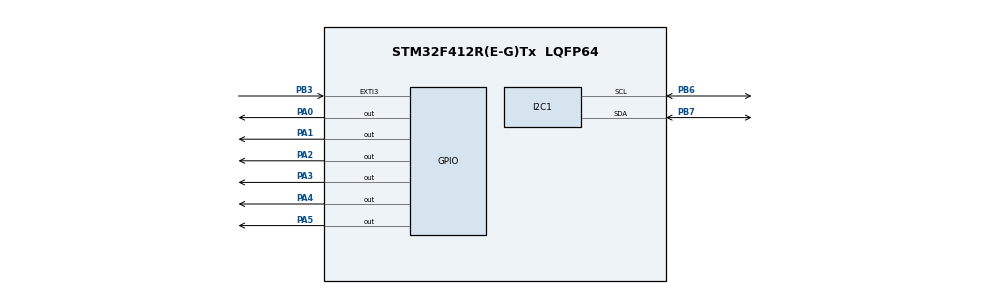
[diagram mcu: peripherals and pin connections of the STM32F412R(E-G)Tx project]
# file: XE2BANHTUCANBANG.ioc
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Mcu.Family=STM32F4
Mcu.Name=STM32F412R(E-G)Tx
Mcu.Package=LQFP64
NVIC.PriorityGroup=NVIC_PRIORITYGROUP_4
PA0.Signal=GPIO_Output
PA1.Signal=GPIO_Output
PA2.Signal=GPIO_Output
PA3.Signal=GPIO_Output
PA4.Signal=GPIO_Output
PA5.Signal=GPIO_Output
PB3.Signal=GPXTI3
PB6.Mode=I2C
PB6.Signal=I2C1_SCL
PB7.Mode=I2C
PB7.Signal=I2C1_SDA
PC14-OSC32_IN.Mode=LSE-External-Oscillator
PC14-OSC32_IN.Signal=RCC_OSC32_IN
PC15-OSC32_OUT.Mode=LSE-External-Oscillator
PC15-OSC32_OUT.Signal=RCC_OSC32_OUT
PH0\ -\ OSC_IN.Mode=HSE-External-Oscillator
PH0\ -\ OSC_IN.Signal=RCC_OSC_IN
PH1\ -\ OSC_OUT.Mode=HSE-External-Oscillator
PH1\ -\ OSC_OUT.Signal=RCC_OSC_OUT
ProjectManager.HeapSize=0x200
ProjectManager.StackSize=0x400
ProjectManager.TargetToolchain=CMake
RCC.AHBFreq_Value=64000000
RCC.APB1CLKDivider=RCC_HCLK_DIV2
RCC.APB1Freq_Value=32000000
RCC.APB1TimFreq_Value=64000000
RCC.APB2CLKDivider=RCC_HCLK_DIV2
RCC.APB2Freq_Value=32000000
RCC.APB2TimFreq_Value=64000000
RCC.CortexFreq_Value=64000000
RCC.HCLKFreq_Value=64000000
RCC.HSE_VALUE=8000000
RCC.PLLM=8
RCC.PLLN=64
RCC.SYSCLKFreq_VALUE=64000000
RCC.SYSCLKSource=RCC_SYSCLKSOURCE_PLLCLK
RCC.USBFreq_Value=64000000
RCC.VCOOutputFreq_Value=128000000
board=custom

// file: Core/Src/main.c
/* USER CODE BEGIN Header */
/**
  ******************************************************************************
  * @file           : main.c
  * @brief          : Main program body
  ******************************************************************************
  * @attention
  *
  * Copyright (c) 2026 STMicroelectronics.
  * All rights reserved.
  *
  * This software is licensed under terms that can be found in the LICENSE file
  * in the root directory of this software component.
  * If no LICENSE file comes with this software, it is provided AS-IS.
  *
  ******************************************************************************
  */
/* USER CODE END Header */
#include "main.h"

/* USER CODE BEGIN Includes */
#include "app_main.h"
/* USER CODE END Includes */

I2C_HandleTypeDef hi2c1;

void SystemClock_Config(void);
static void MX_GPIO_Init(void);
static void MX_I2C1_Init(void);

int main(void)
{

  /* MCU Configuration--------------------------------------------------------*/

  /* Reset of all peripherals, Initializes the Flash interface and the Systick. */
  HAL_Init();

  /* Configure the system clock */
  SystemClock_Config();

  /* Initialize all configured peripherals */
  MX_GPIO_Init();
  MX_I2C1_Init();
  /* USER CODE BEGIN 2 */
  app_init();
  /* USER CODE END 2 */

  /* Infinite loop */
  while (1)
  {

    /* USER CODE BEGIN 3 */
    app_loop();
  }
  /* USER CODE END 3 */
}

void SystemClock_Config(void)
{
  RCC_OscInitTypeDef RCC_OscInitStruct = {0};
  RCC_ClkInitTypeDef RCC_ClkInitStruct = {0};

  /** Configure the main internal regulator output voltage
  */
  __HAL_RCC_PWR_CLK_ENABLE();
  __HAL_PWR_VOLTAGESCALING_CONFIG(PWR_REGULATOR_VOLTAGE_SCALE1);

  /** Initializes the RCC Oscillators according to the specified parameters
  * in the RCC_OscInitTypeDef structure.
  */
  RCC_OscInitStruct.OscillatorType = RCC_OSCILLATORTYPE_HSI;
  RCC_OscInitStruct.HSIState = RCC_HSI_ON;
  RCC_OscInitStruct.HSICalibrationValue = RCC_HSICALIBRATION_DEFAULT;
  RCC_OscInitStruct.PLL.PLLState = RCC_PLL_NONE;
  if (HAL_RCC_OscConfig(&RCC_OscInitStruct) != HAL_OK)
  {
    Error_Handler();
  }

  /** Initializes the CPU, AHB and APB buses clocks
  */
  RCC_ClkInitStruct.ClockType = RCC_CLOCKTYPE_HCLK|RCC_CLOCKTYPE_SYSCLK
                              |RCC_CLOCKTYPE_PCLK1|RCC_CLOCKTYPE_PCLK2;
  RCC_ClkInitStruct.SYSCLKSource = RCC_SYSCLKSOURCE_HSI;
  RCC_ClkInitStruct.AHBCLKDivider = RCC_SYSCLK_DIV1;
  RCC_ClkInitStruct.APB1CLKDivider = RCC_HCLK_DIV1;
  RCC_ClkInitStruct.APB2CLKDivider = RCC_HCLK_DIV1;

  if (HAL_RCC_ClockConfig(&RCC_ClkInitStruct, FLASH_LATENCY_0) != HAL_OK)
  {
    Error_Handler();
  }
}

static void MX_I2C1_Init(void)
{

  hi2c1.Instance = I2C1;
  hi2c1.Init.ClockSpeed = 100000;
  hi2c1.Init.DutyCycle = I2C_DUTYCYCLE_2;
  hi2c1.Init.OwnAddress1 = 0;
  hi2c1.Init.AddressingMode = I2C_ADDRESSINGMODE_7BIT;
  hi2c1.Init.DualAddressMode = I2C_DUALADDRESS_DISABLE;
  hi2c1.Init.OwnAddress2 = 0;
  hi2c1.Init.GeneralCallMode = I2C_GENERALCALL_DISABLE;
  hi2c1.Init.NoStretchMode = I2C_NOSTRETCH_DISABLE;
  if (HAL_I2C_Init(&hi2c1) != HAL_OK)
  {
    Error_Handler();
  }

}

static void MX_GPIO_Init(void)
{
  GPIO_InitTypeDef GPIO_InitStruct = {0};

  /* GPIO Ports Clock Enable */
  __HAL_RCC_GPIOC_CLK_ENABLE();
  __HAL_RCC_GPIOH_CLK_ENABLE();
  __HAL_RCC_GPIOA_CLK_ENABLE();
  __HAL_RCC_GPIOB_CLK_ENABLE();

  /*Configure GPIO pin Output Level */
  HAL_GPIO_WritePin(GPIOA, GPIO_PIN_0|GPIO_PIN_1|GPIO_PIN_2|GPIO_PIN_3
                          |GPIO_PIN_4|GPIO_PIN_5, GPIO_PIN_RESET);

  /*Configure GPIO pins : PA0 PA1 PA2 PA3
                           PA4 PA5 */
  GPIO_InitStruct.Pin = GPIO_PIN_0|GPIO_PIN_1|GPIO_PIN_2|GPIO_PIN_3
                          |GPIO_PIN_4|GPIO_PIN_5;
  GPIO_InitStruct.Mode = GPIO_MODE_OUTPUT_PP;
  GPIO_InitStruct.Pull = GPIO_NOPULL;
  GPIO_InitStruct.Speed = GPIO_SPEED_FREQ_LOW;
  HAL_GPIO_Init(GPIOA, &GPIO_InitStruct);

  /*Configure GPIO pin : PB3 */
  GPIO_InitStruct.Pin = GPIO_PIN_3;
  GPIO_InitStruct.Mode = GPIO_MODE_IT_RISING;
  GPIO_InitStruct.Pull = GPIO_NOPULL;
  HAL_GPIO_Init(GPIOB, &GPIO_InitStruct);

}

void Error_Handler(void)
{
  __disable_irq();
  while (1)
  {
  }
}
